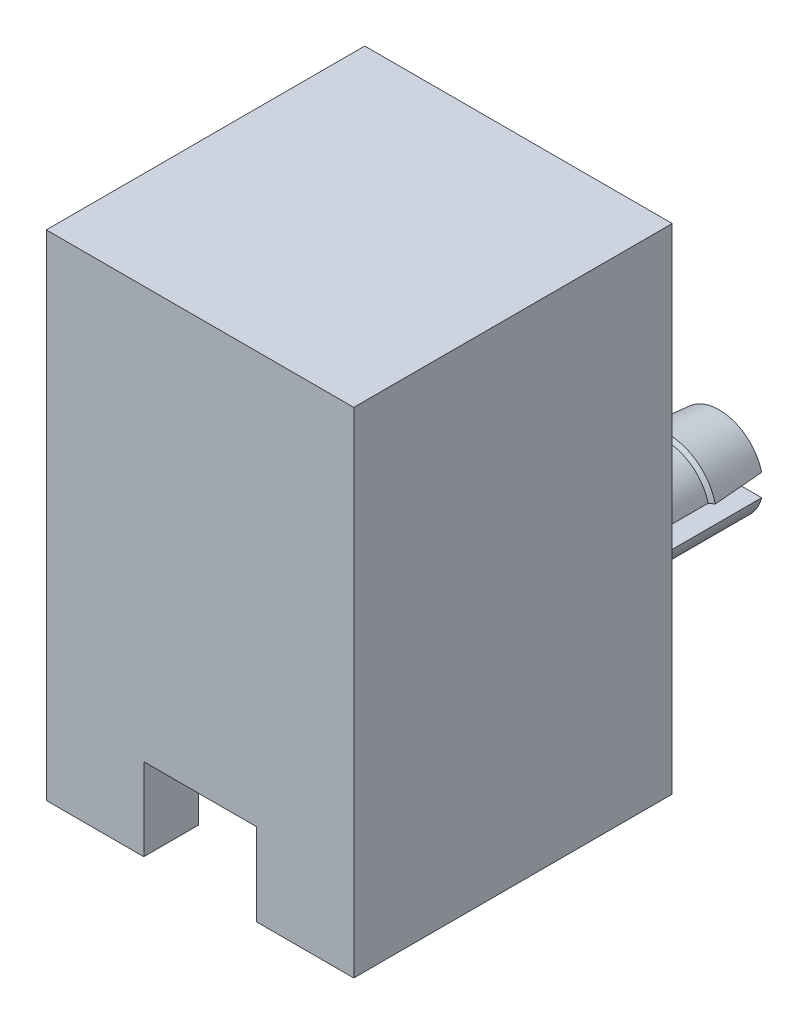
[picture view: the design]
ISO-10303-21;
HEADER;
FILE_DESCRIPTION(('STEP AP214'),'2;1');
FILE_NAME('part.step','',(''),(''),'','','');
FILE_SCHEMA(('AUTOMOTIVE_DESIGN { 1 0 10303 214 1 1 1 1 }'));
ENDSEC;
DATA;
#1=APPLICATION_CONTEXT('core data for automotive mechanical design processes');
#2=APPLICATION_PROTOCOL_DEFINITION('international standard','automotive_design',2000,#1);
#3=PRODUCT_CONTEXT('',#1,'mechanical');
#4=PRODUCT('Part','Part','',(#3));
#5=PRODUCT_RELATED_PRODUCT_CATEGORY('part','',(#4));
#6=PRODUCT_DEFINITION_FORMATION('','',#4);
#7=PRODUCT_DEFINITION_CONTEXT('part definition',#1,'design');
#8=PRODUCT_DEFINITION('design','',#6,#7);
#9=PRODUCT_DEFINITION_SHAPE('','',#8);
#10=(LENGTH_UNIT() NAMED_UNIT(*) SI_UNIT(.MILLI.,.METRE.));
#11=(NAMED_UNIT(*) PLANE_ANGLE_UNIT() SI_UNIT($,.RADIAN.));
#12=(NAMED_UNIT(*) SI_UNIT($,.STERADIAN.) SOLID_ANGLE_UNIT());
#13=UNCERTAINTY_MEASURE_WITH_UNIT(LENGTH_MEASURE(1.E-05),#10,'distance_accuracy_value','');
#14=(GEOMETRIC_REPRESENTATION_CONTEXT(3) GLOBAL_UNCERTAINTY_ASSIGNED_CONTEXT((#13)) GLOBAL_UNIT_ASSIGNED_CONTEXT((#10,
#11,#12)) REPRESENTATION_CONTEXT('',''));
#15=CARTESIAN_POINT('',(0.,0.,0.));
#16=DIRECTION('',(0.,0.,1.));
#17=DIRECTION('',(1.,0.,0.));
#18=AXIS2_PLACEMENT_3D('',#15,#16,#17);
#19=CARTESIAN_POINT('',(0.,0.,-9.3000000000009));
#20=DIRECTION('',(0.,0.,-1.));
#21=DIRECTION('',(-1.,0.,0.));
#22=AXIS2_PLACEMENT_3D('',#19,#20,#21);
#23=PLANE('',#22);
#24=DIRECTION('',(1.,0.,0.));
#25=VECTOR('',#24,1.);
#26=CARTESIAN_POINT('',(6.99772335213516,7.48000000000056,-9.3000000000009));
#27=LINE('',#26,#25);
#28=CARTESIAN_POINT('',(2.26080666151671,7.48000000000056,-9.3000000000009));
#29=VERTEX_POINT('',#28);
#30=CARTESIAN_POINT('',(5.35919333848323,7.48000000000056,-9.3000000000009));
#31=VERTEX_POINT('',#30);
#32=EDGE_CURVE('E484',#29,#31,#27,.T.);
#33=ORIENTED_EDGE('',*,*,#32,.T.);
#34=CARTESIAN_POINT('',(3.81,7.87999999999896,-9.3000000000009));
#35=DIRECTION('',(0.,0.,-1.));
#36=DIRECTION('',(-1.,0.,0.));
#37=AXIS2_PLACEMENT_3D('',#34,#35,#36);
#38=CIRCLE('',#37,1.59999999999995);
#39=EDGE_CURVE('E489',#29,#31,#38,.F.);
#40=ORIENTED_EDGE('',*,*,#39,.F.);
#41=EDGE_LOOP('',(#33,#40));
#42=FACE_BOUND('',#41,.T.);
#43=ADVANCED_FACE('F17',(#42),#23,.T.);
#44=CARTESIAN_POINT('',(0.,0.,-9.3000000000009));
#45=DIRECTION('',(0.,0.,-1.));
#46=DIRECTION('',(-1.,0.,0.));
#47=AXIS2_PLACEMENT_3D('',#44,#45,#46);
#48=PLANE('',#47);
#49=DIRECTION('',(1.,0.,0.));
#50=VECTOR('',#49,1.);
#51=CARTESIAN_POINT('',(6.99772335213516,7.48000000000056,-9.3000000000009));
#52=LINE('',#51,#50);
#53=CARTESIAN_POINT('',(-5.35919333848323,7.48000000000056,-9.3000000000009));
#54=VERTEX_POINT('',#53);
#55=CARTESIAN_POINT('',(-2.26080666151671,7.48000000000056,-9.3000000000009));
#56=VERTEX_POINT('',#55);
#57=EDGE_CURVE('E478',#54,#56,#52,.T.);
#58=ORIENTED_EDGE('',*,*,#57,.T.);
#59=CARTESIAN_POINT('',(-3.81,7.87999999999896,-9.3000000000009));
#60=DIRECTION('',(0.,0.,-1.));
#61=DIRECTION('',(-1.,0.,0.));
#62=AXIS2_PLACEMENT_3D('',#59,#60,#61);
#63=CIRCLE('',#62,1.59999999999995);
#64=EDGE_CURVE('E291',#54,#56,#63,.F.);
#65=ORIENTED_EDGE('',*,*,#64,.F.);
#66=EDGE_LOOP('',(#58,#65));
#67=FACE_BOUND('',#66,.T.);
#68=ADVANCED_FACE('F309',(#67),#48,.T.);
#69=CARTESIAN_POINT('',(-3.81,7.87999999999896,-7.45365044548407));
#70=DIRECTION('',(0.,0.,-1.));
#71=DIRECTION('',(-1.,0.,0.));
#72=AXIS2_PLACEMENT_3D('',#69,#70,#71);
#73=CONICAL_SURFACE('',#72,1.74999999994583,0.966134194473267);
#74=CARTESIAN_POINT('',(-5.51367250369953,8.2799999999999,-7.45365044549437));
#75=CARTESIAN_POINT('',(-5.48794766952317,8.2799999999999,-7.43634304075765));
#76=CARTESIAN_POINT('',(-5.46221198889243,8.2799999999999,-7.41905180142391));
#77=CARTESIAN_POINT('',(-5.4107189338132,8.2799999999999,-7.3845016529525));
#78=CARTESIAN_POINT('',(-5.38496155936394,8.2799999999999,-7.36724274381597));
#79=CARTESIAN_POINT('',(-5.35919333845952,8.2799999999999,-7.35000000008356));
#80=B_SPLINE_CURVE_WITH_KNOTS('',3,(#74,#75,#76,#77,#78,#79),.UNSPECIFIED.,.F.,.F.,(4,2,4),(0.,
0.0930151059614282,0.186030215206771),.UNSPECIFIED.);
#81=CARTESIAN_POINT('',(-5.5136725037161,8.2799999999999,-7.45365044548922));
#82=VERTEX_POINT('',#81);
#83=CARTESIAN_POINT('',(-5.35919333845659,8.2799999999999,-7.35000000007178));
#84=VERTEX_POINT('',#83);
#85=EDGE_CURVE('E263',#82,#84,#80,.T.);
#86=ORIENTED_EDGE('',*,*,#85,.T.);
#87=CARTESIAN_POINT('',(-3.81,7.87999999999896,-7.35000000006));
#88=DIRECTION('',(0.,0.,-1.));
#89=DIRECTION('',(-1.,0.,0.));
#90=AXIS2_PLACEMENT_3D('',#87,#88,#89);
#91=CIRCLE('',#90,1.59999999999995);
#92=CARTESIAN_POINT('',(-2.26080666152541,8.2799999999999,-7.35000000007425));
#93=VERTEX_POINT('',#92);
#94=EDGE_CURVE('E261',#93,#84,#91,.F.);
#95=ORIENTED_EDGE('',*,*,#94,.F.);
#96=CARTESIAN_POINT('',(-2.26080666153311,8.2799999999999,-7.3500000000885));
#97=CARTESIAN_POINT('',(-2.23503844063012,8.2799999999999,-7.36724274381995));
#98=CARTESIAN_POINT('',(-2.20928106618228,8.2799999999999,-7.38450165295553));
#99=CARTESIAN_POINT('',(-2.1577880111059,8.2799999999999,-7.41905180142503));
#100=CARTESIAN_POINT('',(-2.13205233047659,8.2799999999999,-7.43634304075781));
#101=CARTESIAN_POINT('',(-2.10632749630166,8.2799999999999,-7.45365044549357));
#102=B_SPLINE_CURVE_WITH_KNOTS('',3,(#96,#97,#98,#99,#100,#101),.UNSPECIFIED.,.F.,.F.,(4,2,4),
(0.,0.0930151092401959,0.186030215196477),.UNSPECIFIED.);
#103=CARTESIAN_POINT('',(-2.10632749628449,8.2799999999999,-7.45365044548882));
#104=VERTEX_POINT('',#103);
#105=EDGE_CURVE('E20',#93,#104,#102,.T.);
#106=ORIENTED_EDGE('',*,*,#105,.T.);
#107=CARTESIAN_POINT('',(-3.81,7.87999999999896,-7.45365044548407));
#108=DIRECTION('',(0.,0.,1.));
#109=DIRECTION('',(0.,-1.,0.));
#110=AXIS2_PLACEMENT_3D('',#107,#108,#109);
#111=CIRCLE('',#110,1.749999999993);
#112=EDGE_CURVE('E258',#82,#104,#111,.F.);
#113=ORIENTED_EDGE('',*,*,#112,.F.);
#114=EDGE_LOOP('',(#86,#95,#106,#113));
#115=FACE_BOUND('',#114,.T.);
#116=ADVANCED_FACE('F257',(#115),#73,.T.);
#117=CARTESIAN_POINT('',(0.,0.,-9.3000000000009));
#118=DIRECTION('',(0.,0.,-1.));
#119=DIRECTION('',(-1.,0.,0.));
#120=AXIS2_PLACEMENT_3D('',#117,#118,#119);
#121=PLANE('',#120);
#122=DIRECTION('',(1.,0.,0.));
#123=VECTOR('',#122,1.);
#124=CARTESIAN_POINT('',(-6.92386875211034,8.2799999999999,-9.29999999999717));
#125=LINE('',#124,#123);
#126=CARTESIAN_POINT('',(-2.26080666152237,8.2799999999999,-9.29999999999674));
#127=VERTEX_POINT('',#126);
#128=CARTESIAN_POINT('',(-5.35919333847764,8.2799999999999,-9.29999999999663));
#129=VERTEX_POINT('',#128);
#130=EDGE_CURVE('E276',#127,#129,#125,.F.);
#131=ORIENTED_EDGE('',*,*,#130,.T.);
#132=CARTESIAN_POINT('',(-3.81,7.87999999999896,-9.29999999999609));
#133=DIRECTION('',(0.,0.,1.));
#134=DIRECTION('',(0.,-1.,0.));
#135=AXIS2_PLACEMENT_3D('',#132,#133,#134);
#136=CIRCLE('',#135,1.59999999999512);
#137=EDGE_CURVE('E273',#127,#129,#136,.T.);
#138=ORIENTED_EDGE('',*,*,#137,.F.);
#139=EDGE_LOOP('',(#131,#138));
#140=FACE_BOUND('',#139,.T.);
#141=ADVANCED_FACE('F301',(#140),#121,.T.);
#142=CARTESIAN_POINT('',(-3.81,7.87999999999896,-7.45365044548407));
#143=DIRECTION('',(0.,0.,1.));
#144=DIRECTION('',(0.,-1.,0.));
#145=AXIS2_PLACEMENT_3D('',#142,#143,#144);
#146=CONICAL_SURFACE('',#145,1.749999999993,0.081063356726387);
#147=CARTESIAN_POINT('',(-5.35919333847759,8.2799999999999,-9.29999999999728));
#148=CARTESIAN_POINT('',(-5.38500925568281,8.2799999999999,-8.99228087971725));
#149=CARTESIAN_POINT('',(-5.410790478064,8.2799999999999,-8.68455885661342));
#150=CARTESIAN_POINT('',(-5.46228353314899,8.2799999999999,-8.06910900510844));
#151=CARTESIAN_POINT('',(-5.48799536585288,8.2799999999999,-7.7613811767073));
#152=CARTESIAN_POINT('',(-5.51367250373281,8.2799999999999,-7.45365044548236));
#153=B_SPLINE_CURVE_WITH_KNOTS('',3,(#147,#148,#149,#150,#151,#152),.UNSPECIFIED.,.F.,.F.,(4,2,
4),(0.,0.926400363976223,1.8528007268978),.UNSPECIFIED.);
#154=EDGE_CURVE('E271',#129,#82,#153,.T.);
#155=ORIENTED_EDGE('',*,*,#154,.T.);
#156=ORIENTED_EDGE('',*,*,#112,.T.);
#157=CARTESIAN_POINT('',(-2.10632749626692,8.2799999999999,-7.45365044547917));
#158=CARTESIAN_POINT('',(-2.1320046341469,8.2799999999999,-7.76138117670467));
#159=CARTESIAN_POINT('',(-2.15771646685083,8.2799999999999,-8.06910900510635));
#160=CARTESIAN_POINT('',(-2.20920952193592,8.2799999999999,-8.68455885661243));
#161=CARTESIAN_POINT('',(-2.23499074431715,8.2799999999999,-8.99228087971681));
#162=CARTESIAN_POINT('',(-2.26080666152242,8.2799999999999,-9.29999999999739));
#163=B_SPLINE_CURVE_WITH_KNOTS('',3,(#157,#158,#159,#160,#161,#162),.UNSPECIFIED.,.F.,.F.,(4,2,
4),(0.,0.926400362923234,1.85280072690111),.UNSPECIFIED.);
#164=EDGE_CURVE('E268',#104,#127,#163,.T.);
#165=ORIENTED_EDGE('',*,*,#164,.T.);
#166=ORIENTED_EDGE('',*,*,#137,.T.);
#167=EDGE_LOOP('',(#155,#156,#165,#166));
#168=FACE_BOUND('',#167,.T.);
#169=ADVANCED_FACE('F266',(#168),#146,.T.);
#170=CARTESIAN_POINT('',(3.81,7.87999999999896,-7.45365044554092));
#171=DIRECTION('',(0.,0.,-1.));
#172=DIRECTION('',(0.,1.,0.));
#173=AXIS2_PLACEMENT_3D('',#170,#171,#172);
#174=CONICAL_SURFACE('',#173,1.75000000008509,0.966134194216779);
#175=CARTESIAN_POINT('',(5.35919333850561,8.2799999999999,-7.35000000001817));
#176=CARTESIAN_POINT('',(5.38496155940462,8.2799999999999,-7.36724274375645));
#177=CARTESIAN_POINT('',(5.41071893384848,8.2799999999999,-7.38450165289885));
#178=CARTESIAN_POINT('',(5.46221198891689,8.2799999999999,-7.41905180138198));
#179=CARTESIAN_POINT('',(5.48794766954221,8.2799999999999,-7.43634304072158));
#180=CARTESIAN_POINT('',(5.51367250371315,8.2799999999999,-7.45365044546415));
#181=B_SPLINE_CURVE_WITH_KNOTS('',3,(#175,#176,#177,#178,#179,#180),.UNSPECIFIED.,.F.,.F.,(4,2,
4),(0.,0.0930151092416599,0.186030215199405),.UNSPECIFIED.);
#182=CARTESIAN_POINT('',(5.3591933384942,8.2799999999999,-7.34999999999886));
#183=VERTEX_POINT('',#182);
#184=CARTESIAN_POINT('',(5.51367250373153,8.2799999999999,-7.45365044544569));
#185=VERTEX_POINT('',#184);
#186=EDGE_CURVE('E321',#183,#185,#181,.T.);
#187=ORIENTED_EDGE('',*,*,#186,.T.);
#188=CARTESIAN_POINT('',(3.81,7.87999999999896,-7.45365044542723));
#189=DIRECTION('',(0.,0.,1.));
#190=DIRECTION('',(1.,0.,0.));
#191=AXIS2_PLACEMENT_3D('',#188,#189,#190);
#192=CIRCLE('',#191,1.75000000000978);
#193=CARTESIAN_POINT('',(2.1063274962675,8.2799999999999,-7.45365044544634));
#194=VERTEX_POINT('',#193);
#195=EDGE_CURVE('E538',#194,#185,#192,.F.);
#196=ORIENTED_EDGE('',*,*,#195,.F.);
#197=CARTESIAN_POINT('',(2.10632749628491,8.2799999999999,-7.45365044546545));
#198=CARTESIAN_POINT('',(2.1320523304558,8.2799999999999,-7.43634304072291));
#199=CARTESIAN_POINT('',(2.15778801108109,8.2799999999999,-7.41905180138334));
#200=CARTESIAN_POINT('',(2.20928106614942,8.2799999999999,-7.38450165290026));
#201=CARTESIAN_POINT('',(2.23503844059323,8.2799999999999,-7.36724274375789));
#202=CARTESIAN_POINT('',(2.2608066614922,8.2799999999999,-7.35000000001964));
#203=B_SPLINE_CURVE_WITH_KNOTS('',3,(#197,#198,#199,#200,#201,#202),.UNSPECIFIED.,.F.,.F.,(4,2,
4),(0.,0.0930151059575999,0.186030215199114),.UNSPECIFIED.);
#204=CARTESIAN_POINT('',(2.26080666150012,8.2799999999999,-7.34999999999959));
#205=VERTEX_POINT('',#204);
#206=EDGE_CURVE('E272',#194,#205,#203,.T.);
#207=ORIENTED_EDGE('',*,*,#206,.T.);
#208=CARTESIAN_POINT('',(3.81,7.87999999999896,-7.34999999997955));
#209=DIRECTION('',(0.,0.,-1.));
#210=DIRECTION('',(-1.,0.,0.));
#211=AXIS2_PLACEMENT_3D('',#208,#209,#210);
#212=CIRCLE('',#211,1.59999999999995);
#213=EDGE_CURVE('E472',#183,#205,#212,.F.);
#214=ORIENTED_EDGE('',*,*,#213,.F.);
#215=EDGE_LOOP('',(#187,#196,#207,#214));
#216=FACE_BOUND('',#215,.T.);
#217=ADVANCED_FACE('F300',(#216),#174,.T.);
#218=CARTESIAN_POINT('',(0.,0.,-9.3000000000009));
#219=DIRECTION('',(0.,0.,-1.));
#220=DIRECTION('',(-1.,0.,0.));
#221=AXIS2_PLACEMENT_3D('',#218,#219,#220);
#222=PLANE('',#221);
#223=DIRECTION('',(1.,0.,0.));
#224=VECTOR('',#223,1.);
#225=CARTESIAN_POINT('',(-6.92386875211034,8.2799999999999,-9.29999999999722));
#226=LINE('',#225,#224);
#227=CARTESIAN_POINT('',(5.35919333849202,8.2799999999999,-9.29999999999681));
#228=VERTEX_POINT('',#227);
#229=CARTESIAN_POINT('',(2.26080666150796,8.2799999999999,-9.29999999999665));
#230=VERTEX_POINT('',#229);
#231=EDGE_CURVE('E349',#228,#230,#226,.F.);
#232=ORIENTED_EDGE('',*,*,#231,.T.);
#233=CARTESIAN_POINT('',(3.81,7.87999999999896,-9.29999999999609));
#234=DIRECTION('',(0.,0.,1.));
#235=DIRECTION('',(1.,0.,0.));
#236=AXIS2_PLACEMENT_3D('',#233,#234,#235);
#237=CIRCLE('',#236,1.60000000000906);
#238=EDGE_CURVE('E534',#228,#230,#237,.T.);
#239=ORIENTED_EDGE('',*,*,#238,.F.);
#240=EDGE_LOOP('',(#232,#239));
#241=FACE_BOUND('',#240,.T.);
#242=ADVANCED_FACE('F356',(#241),#222,.T.);
#243=CARTESIAN_POINT('',(3.81,7.87999999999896,-7.45365044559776));
#244=DIRECTION('',(0.,0.,1.));
#245=DIRECTION('',(1.,0.,0.));
#246=AXIS2_PLACEMENT_3D('',#243,#244,#245);
#247=CONICAL_SURFACE('',#246,1.74999999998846,0.0810633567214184);
#248=CARTESIAN_POINT('',(5.51367250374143,8.2799999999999,-7.45365044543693));
#249=CARTESIAN_POINT('',(5.48799536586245,8.2799999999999,-7.76138117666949));
#250=CARTESIAN_POINT('',(5.46228353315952,8.2799999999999,-8.06910900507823));
#251=CARTESIAN_POINT('',(5.41079047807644,8.2799999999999,-8.68455885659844));
#252=CARTESIAN_POINT('',(5.38500925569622,8.2799999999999,-8.99228087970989));
#253=CARTESIAN_POINT('',(5.35919333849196,8.2799999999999,-9.29999999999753));
#254=B_SPLINE_CURVE_WITH_KNOTS('',3,(#248,#249,#250,#251,#252,#253),.UNSPECIFIED.,.F.,.F.,(4,2,
4),(0.,0.926400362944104,1.85280072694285),.UNSPECIFIED.);
#255=EDGE_CURVE('E344',#185,#228,#254,.T.);
#256=ORIENTED_EDGE('',*,*,#255,.T.);
#257=ORIENTED_EDGE('',*,*,#238,.T.);
#258=CARTESIAN_POINT('',(2.26080666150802,8.2799999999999,-9.2999999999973));
#259=CARTESIAN_POINT('',(2.23499074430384,8.2799999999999,-8.99228087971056));
#260=CARTESIAN_POINT('',(2.20920952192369,8.2799999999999,-8.6845588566));
#261=CARTESIAN_POINT('',(2.15771646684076,8.2799999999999,-8.06910900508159));
#262=CARTESIAN_POINT('',(2.1320046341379,8.2799999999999,-7.76138117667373));
#263=CARTESIAN_POINT('',(2.106327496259,8.2799999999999,-7.45365044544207));
#264=B_SPLINE_CURVE_WITH_KNOTS('',3,(#258,#259,#260,#261,#262,#263),.UNSPECIFIED.,.F.,.F.,(4,2,
4),(0.,0.926400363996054,1.85280072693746),.UNSPECIFIED.);
#265=EDGE_CURVE('E338',#230,#194,#264,.T.);
#266=ORIENTED_EDGE('',*,*,#265,.T.);
#267=ORIENTED_EDGE('',*,*,#195,.T.);
#268=EDGE_LOOP('',(#256,#257,#266,#267));
#269=FACE_BOUND('',#268,.T.);
#270=ADVANCED_FACE('F351',(#269),#247,.T.);
#271=CARTESIAN_POINT('',(2.9000000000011,0.,-3.0000000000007));
#272=DIRECTION('',(0.,0.,-1.));
#273=DIRECTION('',(-1.,0.,0.));
#274=AXIS2_PLACEMENT_3D('',#271,#272,#273);
#275=PLANE('',#274);
#276=DIRECTION('',(1.,0.,0.));
#277=VECTOR('',#276,1.);
#278=CARTESIAN_POINT('',(0.,10.0000000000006,-3.0000000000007));
#279=LINE('',#278,#277);
#280=CARTESIAN_POINT('',(2.9000000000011,10.0000000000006,-3.0000000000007));
#281=VERTEX_POINT('',#280);
#282=CARTESIAN_POINT('',(3.99999999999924,10.0000000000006,-3.0000000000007));
#283=VERTEX_POINT('',#282);
#284=EDGE_CURVE('E527',#281,#283,#279,.T.);
#285=ORIENTED_EDGE('',*,*,#284,.F.);
#286=DIRECTION('',(0.,1.,0.));
#287=VECTOR('',#286,1.);
#288=CARTESIAN_POINT('',(2.9000000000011,0.,-3.0000000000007));
#289=LINE('',#288,#287);
#290=CARTESIAN_POINT('',(2.9000000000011,0.,-3.0000000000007));
#291=VERTEX_POINT('',#290);
#292=EDGE_CURVE('E460',#281,#291,#289,.F.);
#293=ORIENTED_EDGE('',*,*,#292,.T.);
#294=DIRECTION('',(-1.,0.,0.));
#295=VECTOR('',#294,1.);
#296=CARTESIAN_POINT('',(2.9000000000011,0.,-3.0000000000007));
#297=LINE('',#296,#295);
#298=CARTESIAN_POINT('',(3.99999999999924,0.,-3.0000000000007));
#299=VERTEX_POINT('',#298);
#300=EDGE_CURVE('E532',#299,#291,#297,.T.);
#301=ORIENTED_EDGE('',*,*,#300,.F.);
#302=DIRECTION('',(0.,1.,0.));
#303=VECTOR('',#302,1.);
#304=CARTESIAN_POINT('',(3.99999999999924,0.,-3.0000000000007));
#305=LINE('',#304,#303);
#306=EDGE_CURVE('E518',#299,#283,#305,.T.);
#307=ORIENTED_EDGE('',*,*,#306,.T.);
#308=EDGE_LOOP('',(#285,#293,#301,#307));
#309=FACE_BOUND('',#308,.T.);
#310=ADVANCED_FACE('F355',(#309),#275,.F.);
#311=CARTESIAN_POINT('',(-3.99999999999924,0.,-3.0000000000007));
#312=DIRECTION('',(0.,0.,-1.));
#313=DIRECTION('',(-1.,0.,0.));
#314=AXIS2_PLACEMENT_3D('',#311,#312,#313);
#315=PLANE('',#314);
#316=DIRECTION('',(1.,0.,0.));
#317=VECTOR('',#316,1.);
#318=CARTESIAN_POINT('',(0.,10.0000000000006,-3.0000000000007));
#319=LINE('',#318,#317);
#320=CARTESIAN_POINT('',(-3.99999999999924,10.0000000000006,-3.0000000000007));
#321=VERTEX_POINT('',#320);
#322=CARTESIAN_POINT('',(-2.9000000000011,10.0000000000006,-3.0000000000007));
#323=VERTEX_POINT('',#322);
#324=EDGE_CURVE('E524',#321,#323,#319,.T.);
#325=ORIENTED_EDGE('',*,*,#324,.F.);
#326=DIRECTION('',(0.,1.,0.));
#327=VECTOR('',#326,1.);
#328=CARTESIAN_POINT('',(-3.99999999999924,0.,-3.0000000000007));
#329=LINE('',#328,#327);
#330=CARTESIAN_POINT('',(-3.99999999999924,0.,-3.0000000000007));
#331=VERTEX_POINT('',#330);
#332=EDGE_CURVE('E500',#321,#331,#329,.F.);
#333=ORIENTED_EDGE('',*,*,#332,.T.);
#334=DIRECTION('',(-1.,0.,0.));
#335=VECTOR('',#334,1.);
#336=CARTESIAN_POINT('',(-3.99999999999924,0.,-3.0000000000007));
#337=LINE('',#336,#335);
#338=CARTESIAN_POINT('',(-2.9000000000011,0.,-3.0000000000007));
#339=VERTEX_POINT('',#338);
#340=EDGE_CURVE('E530',#339,#331,#337,.T.);
#341=ORIENTED_EDGE('',*,*,#340,.F.);
#342=DIRECTION('',(0.,1.,0.));
#343=VECTOR('',#342,1.);
#344=CARTESIAN_POINT('',(-2.9000000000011,0.,-3.0000000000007));
#345=LINE('',#344,#343);
#346=EDGE_CURVE('E452',#339,#323,#345,.T.);
#347=ORIENTED_EDGE('',*,*,#346,.T.);
#348=EDGE_LOOP('',(#325,#333,#341,#347));
#349=FACE_BOUND('',#348,.T.);
#350=ADVANCED_FACE('F726',(#349),#315,.F.);
#351=CARTESIAN_POINT('',(0.,10.0000000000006,0.));
#352=DIRECTION('',(0.,-1.,0.));
#353=DIRECTION('',(0.,0.,-1.));
#354=AXIS2_PLACEMENT_3D('',#351,#352,#353);
#355=PLANE('',#354);
#356=DIRECTION('',(0.,0.,1.));
#357=VECTOR('',#356,1.);
#358=CARTESIAN_POINT('',(-2.9000000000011,10.0000000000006,-3.0000000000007));
#359=LINE('',#358,#357);
#360=CARTESIAN_POINT('',(-2.9000000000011,10.0000000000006,-4.80000000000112));
#361=VERTEX_POINT('',#360);
#362=EDGE_CURVE('E447',#323,#361,#359,.F.);
#363=ORIENTED_EDGE('',*,*,#362,.T.);
#364=DIRECTION('',(-1.,0.,0.));
#365=VECTOR('',#364,1.);
#366=CARTESIAN_POINT('',(-2.9000000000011,10.0000000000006,-4.80000000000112));
#367=LINE('',#366,#365);
#368=CARTESIAN_POINT('',(2.9000000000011,10.0000000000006,-4.80000000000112));
#369=VERTEX_POINT('',#368);
#370=EDGE_CURVE('E522',#361,#369,#367,.F.);
#371=ORIENTED_EDGE('',*,*,#370,.T.);
#372=DIRECTION('',(0.,0.,-1.));
#373=VECTOR('',#372,1.);
#374=CARTESIAN_POINT('',(2.9000000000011,10.0000000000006,-4.80000000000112));
#375=LINE('',#374,#373);
#376=EDGE_CURVE('E463',#369,#281,#375,.F.);
#377=ORIENTED_EDGE('',*,*,#376,.T.);
#378=ORIENTED_EDGE('',*,*,#284,.T.);
#379=DIRECTION('',(0.,0.,-1.));
#380=VECTOR('',#379,1.);
#381=CARTESIAN_POINT('',(3.99999999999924,10.0000000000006,-3.0000000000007));
#382=LINE('',#381,#380);
#383=CARTESIAN_POINT('',(3.99999999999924,10.0000000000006,3.80000000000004));
#384=VERTEX_POINT('',#383);
#385=EDGE_CURVE('E516',#283,#384,#382,.F.);
#386=ORIENTED_EDGE('',*,*,#385,.T.);
#387=DIRECTION('',(1.,0.,0.));
#388=VECTOR('',#387,1.);
#389=CARTESIAN_POINT('',(3.99999999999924,10.0000000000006,3.80000000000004));
#390=LINE('',#389,#388);
#391=CARTESIAN_POINT('',(-3.99999999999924,10.0000000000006,3.80000000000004));
#392=VERTEX_POINT('',#391);
#393=EDGE_CURVE('E512',#384,#392,#390,.F.);
#394=ORIENTED_EDGE('',*,*,#393,.T.);
#395=DIRECTION('',(0.,0.,1.));
#396=VECTOR('',#395,1.);
#397=CARTESIAN_POINT('',(-3.99999999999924,10.0000000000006,3.80000000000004));
#398=LINE('',#397,#396);
#399=EDGE_CURVE('E503',#392,#321,#398,.F.);
#400=ORIENTED_EDGE('',*,*,#399,.T.);
#401=ORIENTED_EDGE('',*,*,#324,.T.);
#402=EDGE_LOOP('',(#363,#371,#377,#378,#386,#394,#400,#401));
#403=FACE_BOUND('',#402,.T.);
#404=ADVANCED_FACE('F724',(#403),#355,.T.);
#405=CARTESIAN_POINT('',(-2.9000000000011,0.,-4.80000000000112));
#406=DIRECTION('',(0.,0.,-1.));
#407=DIRECTION('',(-1.,0.,0.));
#408=AXIS2_PLACEMENT_3D('',#405,#406,#407);
#409=PLANE('',#408);
#410=ORIENTED_EDGE('',*,*,#370,.F.);
#411=DIRECTION('',(0.,1.,0.));
#412=VECTOR('',#411,1.);
#413=CARTESIAN_POINT('',(-2.9000000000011,0.,-4.80000000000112));
#414=LINE('',#413,#412);
#415=CARTESIAN_POINT('',(-2.9000000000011,4.80000000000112,-4.80000000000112));
#416=VERTEX_POINT('',#415);
#417=EDGE_CURVE('E439',#361,#416,#414,.F.);
#418=ORIENTED_EDGE('',*,*,#417,.T.);
#419=DIRECTION('',(1.,0.,0.));
#420=VECTOR('',#419,1.);
#421=CARTESIAN_POINT('',(-2.9000000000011,4.80000000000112,-4.80000000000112));
#422=LINE('',#421,#420);
#423=CARTESIAN_POINT('',(2.9000000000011,4.80000000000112,-4.80000000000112));
#424=VERTEX_POINT('',#423);
#425=EDGE_CURVE('E426',#416,#424,#422,.T.);
#426=ORIENTED_EDGE('',*,*,#425,.T.);
#427=DIRECTION('',(0.,1.,0.));
#428=VECTOR('',#427,1.);
#429=CARTESIAN_POINT('',(2.9000000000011,0.,-4.80000000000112));
#430=LINE('',#429,#428);
#431=EDGE_CURVE('E466',#424,#369,#430,.T.);
#432=ORIENTED_EDGE('',*,*,#431,.T.);
#433=EDGE_LOOP('',(#410,#418,#426,#432));
#434=FACE_BOUND('',#433,.T.);
#435=ADVANCED_FACE('F720',(#434),#409,.F.);
#436=CARTESIAN_POINT('',(-2.9000000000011,0.,-4.80000000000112));
#437=DIRECTION('',(0.,0.,-1.));
#438=DIRECTION('',(-1.,0.,0.));
#439=AXIS2_PLACEMENT_3D('',#436,#437,#438);
#440=PLANE('',#439);
#441=DIRECTION('',(0.,1.,0.));
#442=VECTOR('',#441,1.);
#443=CARTESIAN_POINT('',(-2.9000000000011,0.,-4.80000000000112));
#444=LINE('',#443,#442);
#445=CARTESIAN_POINT('',(-2.9000000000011,1.79999999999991,-4.80000000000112));
#446=VERTEX_POINT('',#445);
#447=CARTESIAN_POINT('',(-2.9000000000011,0.,-4.80000000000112));
#448=VERTEX_POINT('',#447);
#449=EDGE_CURVE('E454',#446,#448,#444,.F.);
#450=ORIENTED_EDGE('',*,*,#449,.T.);
#451=DIRECTION('',(-1.,0.,0.));
#452=VECTOR('',#451,1.);
#453=CARTESIAN_POINT('',(-2.9000000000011,0.,-4.80000000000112));
#454=LINE('',#453,#452);
#455=CARTESIAN_POINT('',(-1.5000000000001,0.,-4.80000000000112));
#456=VERTEX_POINT('',#455);
#457=EDGE_CURVE('E520',#456,#448,#454,.T.);
#458=ORIENTED_EDGE('',*,*,#457,.F.);
#459=DIRECTION('',(0.,1.,0.));
#460=VECTOR('',#459,1.);
#461=CARTESIAN_POINT('',(-1.5000000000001,-1.18255143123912,-4.80000000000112));
#462=LINE('',#461,#460);
#463=CARTESIAN_POINT('',(-1.5000000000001,1.79999999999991,-4.80000000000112));
#464=VERTEX_POINT('',#463);
#465=EDGE_CURVE('E626',#456,#464,#462,.T.);
#466=ORIENTED_EDGE('',*,*,#465,.T.);
#467=DIRECTION('',(1.,0.,0.));
#468=VECTOR('',#467,1.);
#469=CARTESIAN_POINT('',(-1.5000000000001,1.79999999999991,-4.80000000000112));
#470=LINE('',#469,#468);
#471=EDGE_CURVE('E443',#464,#446,#470,.F.);
#472=ORIENTED_EDGE('',*,*,#471,.T.);
#473=EDGE_LOOP('',(#450,#458,#466,#472));
#474=FACE_BOUND('',#473,.T.);
#475=ADVANCED_FACE('F716',(#474),#440,.F.);
#476=CARTESIAN_POINT('',(3.99999999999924,0.,-3.0000000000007));
#477=DIRECTION('',(1.,0.,0.));
#478=DIRECTION('',(0.,0.,-1.));
#479=AXIS2_PLACEMENT_3D('',#476,#477,#478);
#480=PLANE('',#479);
#481=ORIENTED_EDGE('',*,*,#385,.F.);
#482=ORIENTED_EDGE('',*,*,#306,.F.);
#483=DIRECTION('',(0.,0.,1.));
#484=VECTOR('',#483,1.);
#485=CARTESIAN_POINT('',(3.99999999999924,0.,0.));
#486=LINE('',#485,#484);
#487=CARTESIAN_POINT('',(3.99999999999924,0.,3.80000000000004));
#488=VERTEX_POINT('',#487);
#489=EDGE_CURVE('E619',#299,#488,#486,.T.);
#490=ORIENTED_EDGE('',*,*,#489,.T.);
#491=DIRECTION('',(0.,1.,0.));
#492=VECTOR('',#491,1.);
#493=CARTESIAN_POINT('',(3.99999999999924,0.,3.80000000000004));
#494=LINE('',#493,#492);
#495=EDGE_CURVE('E509',#488,#384,#494,.T.);
#496=ORIENTED_EDGE('',*,*,#495,.T.);
#497=EDGE_LOOP('',(#481,#482,#490,#496));
#498=FACE_BOUND('',#497,.T.);
#499=ADVANCED_FACE('F712',(#498),#480,.F.);
#500=CARTESIAN_POINT('',(-2.9000000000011,0.,-4.80000000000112));
#501=DIRECTION('',(0.,0.,-1.));
#502=DIRECTION('',(-1.,0.,0.));
#503=AXIS2_PLACEMENT_3D('',#500,#501,#502);
#504=PLANE('',#503);
#505=DIRECTION('',(1.,0.,0.));
#506=VECTOR('',#505,1.);
#507=CARTESIAN_POINT('',(0.,0.,-4.80000000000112));
#508=LINE('',#507,#506);
#509=CARTESIAN_POINT('',(1.5000000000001,0.,-4.80000000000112));
#510=VERTEX_POINT('',#509);
#511=CARTESIAN_POINT('',(2.9000000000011,0.,-4.80000000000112));
#512=VERTEX_POINT('',#511);
#513=EDGE_CURVE('E610',#510,#512,#508,.T.);
#514=ORIENTED_EDGE('',*,*,#513,.T.);
#515=DIRECTION('',(0.,1.,0.));
#516=VECTOR('',#515,1.);
#517=CARTESIAN_POINT('',(2.9000000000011,0.,-4.80000000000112));
#518=LINE('',#517,#516);
#519=CARTESIAN_POINT('',(2.9000000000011,1.79999999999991,-4.80000000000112));
#520=VERTEX_POINT('',#519);
#521=EDGE_CURVE('E435',#512,#520,#518,.T.);
#522=ORIENTED_EDGE('',*,*,#521,.T.);
#523=DIRECTION('',(-1.,0.,0.));
#524=VECTOR('',#523,1.);
#525=CARTESIAN_POINT('',(-2.9000000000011,1.79999999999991,-4.80000000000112));
#526=LINE('',#525,#524);
#527=CARTESIAN_POINT('',(1.5000000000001,1.79999999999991,-4.80000000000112));
#528=VERTEX_POINT('',#527);
#529=EDGE_CURVE('E514',#528,#520,#526,.F.);
#530=ORIENTED_EDGE('',*,*,#529,.F.);
#531=DIRECTION('',(0.,1.,0.));
#532=VECTOR('',#531,1.);
#533=CARTESIAN_POINT('',(1.5000000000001,1.79999999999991,-4.80000000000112));
#534=LINE('',#533,#532);
#535=EDGE_CURVE('E605',#528,#510,#534,.F.);
#536=ORIENTED_EDGE('',*,*,#535,.T.);
#537=EDGE_LOOP('',(#514,#522,#530,#536));
#538=FACE_BOUND('',#537,.T.);
#539=ADVANCED_FACE('F708',(#538),#504,.F.);
#540=CARTESIAN_POINT('',(3.99999999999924,0.,3.80000000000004));
#541=DIRECTION('',(0.,0.,1.));
#542=DIRECTION('',(1.,0.,0.));
#543=AXIS2_PLACEMENT_3D('',#540,#541,#542);
#544=PLANE('',#543);
#545=DIRECTION('',(1.,0.,0.));
#546=VECTOR('',#545,1.);
#547=CARTESIAN_POINT('',(0.,0.,3.80000000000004));
#548=LINE('',#547,#546);
#549=CARTESIAN_POINT('',(2.04999999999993,0.,3.80000000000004));
#550=VERTEX_POINT('',#549);
#551=EDGE_CURVE('E617',#488,#550,#548,.F.);
#552=ORIENTED_EDGE('',*,*,#551,.T.);
#553=DIRECTION('',(0.,1.,0.));
#554=VECTOR('',#553,1.);
#555=CARTESIAN_POINT('',(2.04999999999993,0.,3.80000000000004));
#556=LINE('',#555,#554);
#557=CARTESIAN_POINT('',(2.04999999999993,3.0000000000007,3.80000000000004));
#558=VERTEX_POINT('',#557);
#559=EDGE_CURVE('E490',#550,#558,#556,.T.);
#560=ORIENTED_EDGE('',*,*,#559,.T.);
#561=DIRECTION('',(1.,0.,0.));
#562=VECTOR('',#561,1.);
#563=CARTESIAN_POINT('',(0.,3.0000000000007,3.80000000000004));
#564=LINE('',#563,#562);
#565=CARTESIAN_POINT('',(-2.04999999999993,3.0000000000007,3.80000000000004));
#566=VERTEX_POINT('',#565);
#567=EDGE_CURVE('E492',#566,#558,#564,.T.);
#568=ORIENTED_EDGE('',*,*,#567,.F.);
#569=DIRECTION('',(0.,1.,0.));
#570=VECTOR('',#569,1.);
#571=CARTESIAN_POINT('',(-2.04999999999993,0.,3.80000000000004));
#572=LINE('',#571,#570);
#573=CARTESIAN_POINT('',(-2.04999999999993,0.,3.80000000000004));
#574=VERTEX_POINT('',#573);
#575=EDGE_CURVE('E498',#566,#574,#572,.F.);
#576=ORIENTED_EDGE('',*,*,#575,.T.);
#577=DIRECTION('',(1.,0.,0.));
#578=VECTOR('',#577,1.);
#579=CARTESIAN_POINT('',(0.,0.,3.80000000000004));
#580=LINE('',#579,#578);
#581=CARTESIAN_POINT('',(-3.99999999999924,0.,3.80000000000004));
#582=VERTEX_POINT('',#581);
#583=EDGE_CURVE('E593',#574,#582,#580,.F.);
#584=ORIENTED_EDGE('',*,*,#583,.T.);
#585=DIRECTION('',(0.,1.,0.));
#586=VECTOR('',#585,1.);
#587=CARTESIAN_POINT('',(-3.99999999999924,0.,3.80000000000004));
#588=LINE('',#587,#586);
#589=EDGE_CURVE('E506',#582,#392,#588,.T.);
#590=ORIENTED_EDGE('',*,*,#589,.T.);
#591=ORIENTED_EDGE('',*,*,#393,.F.);
#592=ORIENTED_EDGE('',*,*,#495,.F.);
#593=EDGE_LOOP('',(#552,#560,#568,#576,#584,#590,#591,#592));
#594=FACE_BOUND('',#593,.T.);
#595=ADVANCED_FACE('F704',(#594),#544,.F.);
#596=CARTESIAN_POINT('',(-3.99999999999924,0.,3.80000000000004));
#597=DIRECTION('',(-1.,0.,0.));
#598=DIRECTION('',(0.,0.,1.));
#599=AXIS2_PLACEMENT_3D('',#596,#597,#598);
#600=PLANE('',#599);
#601=ORIENTED_EDGE('',*,*,#399,.F.);
#602=ORIENTED_EDGE('',*,*,#589,.F.);
#603=DIRECTION('',(0.,0.,1.));
#604=VECTOR('',#603,1.);
#605=CARTESIAN_POINT('',(-3.99999999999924,0.,0.));
#606=LINE('',#605,#604);
#607=EDGE_CURVE('E590',#582,#331,#606,.F.);
#608=ORIENTED_EDGE('',*,*,#607,.T.);
#609=ORIENTED_EDGE('',*,*,#332,.F.);
#610=EDGE_LOOP('',(#601,#602,#608,#609));
#611=FACE_BOUND('',#610,.T.);
#612=ADVANCED_FACE('F700',(#611),#600,.F.);
#613=CARTESIAN_POINT('',(-2.04999999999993,0.,6.78417590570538));
#614=DIRECTION('',(-1.,0.,0.));
#615=DIRECTION('',(0.,0.,1.));
#616=AXIS2_PLACEMENT_3D('',#613,#614,#615);
#617=PLANE('',#616);
#618=DIRECTION('',(0.,0.,-1.));
#619=VECTOR('',#618,1.);
#620=CARTESIAN_POINT('',(-2.04999999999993,3.0000000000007,0.));
#621=LINE('',#620,#619);
#622=CARTESIAN_POINT('',(-2.04999999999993,3.0000000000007,5.79999999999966));
#623=VERTEX_POINT('',#622);
#624=EDGE_CURVE('E495',#623,#566,#621,.T.);
#625=ORIENTED_EDGE('',*,*,#624,.F.);
#626=DIRECTION('',(0.,1.,0.));
#627=VECTOR('',#626,1.);
#628=CARTESIAN_POINT('',(-2.04999999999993,0.,5.79999999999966));
#629=LINE('',#628,#627);
#630=CARTESIAN_POINT('',(-2.04999999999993,0.,5.79999999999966));
#631=VERTEX_POINT('',#630);
#632=EDGE_CURVE('E581',#631,#623,#629,.T.);
#633=ORIENTED_EDGE('',*,*,#632,.F.);
#634=DIRECTION('',(0.,0.,1.));
#635=VECTOR('',#634,1.);
#636=CARTESIAN_POINT('',(-2.04999999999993,0.,0.));
#637=LINE('',#636,#635);
#638=EDGE_CURVE('E595',#631,#574,#637,.F.);
#639=ORIENTED_EDGE('',*,*,#638,.T.);
#640=ORIENTED_EDGE('',*,*,#575,.F.);
#641=EDGE_LOOP('',(#625,#633,#639,#640));
#642=FACE_BOUND('',#641,.T.);
#643=ADVANCED_FACE('F696',(#642),#617,.F.);
#644=CARTESIAN_POINT('',(0.,3.0000000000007,0.));
#645=DIRECTION('',(0.,-1.,0.));
#646=DIRECTION('',(0.,0.,-1.));
#647=AXIS2_PLACEMENT_3D('',#644,#645,#646);
#648=PLANE('',#647);
#649=ORIENTED_EDGE('',*,*,#567,.T.);
#650=DIRECTION('',(0.,0.,-1.));
#651=VECTOR('',#650,1.);
#652=CARTESIAN_POINT('',(2.04999999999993,3.0000000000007,3.04286581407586));
#653=LINE('',#652,#651);
#654=CARTESIAN_POINT('',(2.04999999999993,3.0000000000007,5.79999999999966));
#655=VERTEX_POINT('',#654);
#656=EDGE_CURVE('E487',#558,#655,#653,.F.);
#657=ORIENTED_EDGE('',*,*,#656,.T.);
#658=DIRECTION('',(1.,0.,0.));
#659=VECTOR('',#658,1.);
#660=CARTESIAN_POINT('',(-5.60000000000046,3.0000000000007,5.79999999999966));
#661=LINE('',#660,#659);
#662=EDGE_CURVE('E578',#623,#655,#661,.T.);
#663=ORIENTED_EDGE('',*,*,#662,.F.);
#664=ORIENTED_EDGE('',*,*,#624,.T.);
#665=EDGE_LOOP('',(#649,#657,#663,#664));
#666=FACE_BOUND('',#665,.T.);
#667=ADVANCED_FACE('F692',(#666),#648,.T.);
#668=CARTESIAN_POINT('',(2.04999999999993,0.,3.04286581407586));
#669=DIRECTION('',(1.,0.,0.));
#670=DIRECTION('',(0.,0.,-1.));
#671=AXIS2_PLACEMENT_3D('',#668,#669,#670);
#672=PLANE('',#671);
#673=ORIENTED_EDGE('',*,*,#656,.F.);
#674=ORIENTED_EDGE('',*,*,#559,.F.);
#675=DIRECTION('',(0.,0.,1.));
#676=VECTOR('',#675,1.);
#677=CARTESIAN_POINT('',(2.04999999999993,0.,0.));
#678=LINE('',#677,#676);
#679=CARTESIAN_POINT('',(2.04999999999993,0.,5.79999999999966));
#680=VERTEX_POINT('',#679);
#681=EDGE_CURVE('E615',#550,#680,#678,.T.);
#682=ORIENTED_EDGE('',*,*,#681,.T.);
#683=DIRECTION('',(0.,1.,0.));
#684=VECTOR('',#683,1.);
#685=CARTESIAN_POINT('',(2.04999999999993,0.,5.79999999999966));
#686=LINE('',#685,#684);
#687=EDGE_CURVE('E575',#655,#680,#686,.F.);
#688=ORIENTED_EDGE('',*,*,#687,.F.);
#689=EDGE_LOOP('',(#673,#674,#682,#688));
#690=FACE_BOUND('',#689,.T.);
#691=ADVANCED_FACE('F686',(#690),#672,.F.);
#692=CARTESIAN_POINT('',(3.81,7.87999999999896,-5.79999999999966));
#693=DIRECTION('',(0.,0.,-1.));
#694=DIRECTION('',(-1.,0.,0.));
#695=AXIS2_PLACEMENT_3D('',#692,#693,#694);
#696=CYLINDRICAL_SURFACE('',#695,1.59999999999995);
#697=ORIENTED_EDGE('',*,*,#39,.T.);
#698=DIRECTION('',(0.,0.,-1.));
#699=VECTOR('',#698,1.);
#700=CARTESIAN_POINT('',(5.35919333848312,7.48000000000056,-9.3000000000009));
#701=LINE('',#700,#699);
#702=CARTESIAN_POINT('',(5.35919333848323,7.48000000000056,-5.79999999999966));
#703=VERTEX_POINT('',#702);
#704=EDGE_CURVE('E481',#31,#703,#701,.F.);
#705=ORIENTED_EDGE('',*,*,#704,.T.);
#706=CARTESIAN_POINT('',(3.81,7.87999999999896,-5.79999999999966));
#707=DIRECTION('',(0.,0.,-1.));
#708=DIRECTION('',(-1.,0.,0.));
#709=AXIS2_PLACEMENT_3D('',#706,#707,#708);
#710=CIRCLE('',#709,1.59999999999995);
#711=CARTESIAN_POINT('',(2.26080666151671,7.48000000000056,-5.79999999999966));
#712=VERTEX_POINT('',#711);
#713=EDGE_CURVE('E556',#712,#703,#710,.F.);
#714=ORIENTED_EDGE('',*,*,#713,.F.);
#715=DIRECTION('',(0.,0.,-1.));
#716=VECTOR('',#715,1.);
#717=CARTESIAN_POINT('',(2.26080666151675,7.48000000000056,-9.3000000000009));
#718=LINE('',#717,#716);
#719=EDGE_CURVE('E483',#712,#29,#718,.T.);
#720=ORIENTED_EDGE('',*,*,#719,.T.);
#721=EDGE_LOOP('',(#697,#705,#714,#720));
#722=FACE_BOUND('',#721,.T.);
#723=ADVANCED_FACE('F676',(#722),#696,.T.);
#724=CARTESIAN_POINT('',(6.99772335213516,7.48000000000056,-9.3000000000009));
#725=DIRECTION('',(0.,-1.,0.));
#726=DIRECTION('',(0.,0.,-1.));
#727=AXIS2_PLACEMENT_3D('',#724,#725,#726);
#728=PLANE('',#727);
#729=DIRECTION('',(-1.,0.,0.));
#730=VECTOR('',#729,1.);
#731=CARTESIAN_POINT('',(5.60000000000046,7.48000000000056,-5.79999999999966));
#732=LINE('',#731,#730);
#733=EDGE_CURVE('E555',#703,#712,#732,.T.);
#734=ORIENTED_EDGE('',*,*,#733,.F.);
#735=ORIENTED_EDGE('',*,*,#704,.F.);
#736=ORIENTED_EDGE('',*,*,#32,.F.);
#737=ORIENTED_EDGE('',*,*,#719,.F.);
#738=EDGE_LOOP('',(#734,#735,#736,#737));
#739=FACE_BOUND('',#738,.T.);
#740=ADVANCED_FACE('F678',(#739),#728,.F.);
#741=CARTESIAN_POINT('',(-3.81,7.87999999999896,-5.79999999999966));
#742=DIRECTION('',(0.,0.,-1.));
#743=DIRECTION('',(-1.,0.,0.));
#744=AXIS2_PLACEMENT_3D('',#741,#742,#743);
#745=CYLINDRICAL_SURFACE('',#744,1.59999999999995);
#746=ORIENTED_EDGE('',*,*,#64,.T.);
#747=DIRECTION('',(0.,0.,-1.));
#748=VECTOR('',#747,1.);
#749=CARTESIAN_POINT('',(-2.26080666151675,7.48000000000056,-9.3000000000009));
#750=LINE('',#749,#748);
#751=CARTESIAN_POINT('',(-2.26080666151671,7.48000000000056,-5.79999999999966));
#752=VERTEX_POINT('',#751);
#753=EDGE_CURVE('E475',#56,#752,#750,.F.);
#754=ORIENTED_EDGE('',*,*,#753,.T.);
#755=CARTESIAN_POINT('',(-3.81,7.87999999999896,-5.79999999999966));
#756=DIRECTION('',(0.,0.,-1.));
#757=DIRECTION('',(-1.,0.,0.));
#758=AXIS2_PLACEMENT_3D('',#755,#756,#757);
#759=CIRCLE('',#758,1.59999999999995);
#760=CARTESIAN_POINT('',(-5.35919333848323,7.48000000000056,-5.79999999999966));
#761=VERTEX_POINT('',#760);
#762=EDGE_CURVE('E553',#761,#752,#759,.F.);
#763=ORIENTED_EDGE('',*,*,#762,.F.);
#764=DIRECTION('',(0.,0.,-1.));
#765=VECTOR('',#764,1.);
#766=CARTESIAN_POINT('',(-5.35919333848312,7.48000000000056,-9.3000000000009));
#767=LINE('',#766,#765);
#768=EDGE_CURVE('E477',#761,#54,#767,.T.);
#769=ORIENTED_EDGE('',*,*,#768,.T.);
#770=EDGE_LOOP('',(#746,#754,#763,#769));
#771=FACE_BOUND('',#770,.T.);
#772=ADVANCED_FACE('F661',(#771),#745,.T.);
#773=CARTESIAN_POINT('',(6.99772335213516,7.48000000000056,-9.3000000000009));
#774=DIRECTION('',(0.,-1.,0.));
#775=DIRECTION('',(0.,0.,-1.));
#776=AXIS2_PLACEMENT_3D('',#773,#774,#775);
#777=PLANE('',#776);
#778=DIRECTION('',(-1.,0.,0.));
#779=VECTOR('',#778,1.);
#780=CARTESIAN_POINT('',(5.60000000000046,7.48000000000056,-5.79999999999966));
#781=LINE('',#780,#779);
#782=EDGE_CURVE('E552',#752,#761,#781,.T.);
#783=ORIENTED_EDGE('',*,*,#782,.F.);
#784=ORIENTED_EDGE('',*,*,#753,.F.);
#785=ORIENTED_EDGE('',*,*,#57,.F.);
#786=ORIENTED_EDGE('',*,*,#768,.F.);
#787=EDGE_LOOP('',(#783,#784,#785,#786));
#788=FACE_BOUND('',#787,.T.);
#789=ADVANCED_FACE('F657',(#788),#777,.F.);
#790=CARTESIAN_POINT('',(-3.81,7.87999999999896,-5.79999999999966));
#791=DIRECTION('',(0.,0.,-1.));
#792=DIRECTION('',(-1.,0.,0.));
#793=AXIS2_PLACEMENT_3D('',#790,#791,#792);
#794=CYLINDRICAL_SURFACE('',#793,1.59999999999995);
#795=CARTESIAN_POINT('',(-3.81,7.87999999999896,-5.79999999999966));
#796=DIRECTION('',(0.,0.,-1.));
#797=DIRECTION('',(-1.,0.,0.));
#798=AXIS2_PLACEMENT_3D('',#795,#796,#797);
#799=CIRCLE('',#798,1.59999999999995);
#800=CARTESIAN_POINT('',(-2.26080666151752,8.2799999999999,-5.79999999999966));
#801=VERTEX_POINT('',#800);
#802=CARTESIAN_POINT('',(-5.35919333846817,8.2799999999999,-5.79999999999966));
#803=VERTEX_POINT('',#802);
#804=EDGE_CURVE('E549',#801,#803,#799,.F.);
#805=ORIENTED_EDGE('',*,*,#804,.F.);
#806=DIRECTION('',(0.,0.,1.));
#807=VECTOR('',#806,1.);
#808=CARTESIAN_POINT('',(-2.26080666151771,8.2799999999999,-9.3000000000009));
#809=LINE('',#808,#807);
#810=EDGE_CURVE('E277',#801,#93,#809,.F.);
#811=ORIENTED_EDGE('',*,*,#810,.T.);
#812=ORIENTED_EDGE('',*,*,#94,.T.);
#813=DIRECTION('',(0.,0.,1.));
#814=VECTOR('',#813,1.);
#815=CARTESIAN_POINT('',(-5.35919333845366,8.2799999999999,-9.3000000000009));
#816=LINE('',#815,#814);
#817=EDGE_CURVE('E473',#84,#803,#816,.T.);
#818=ORIENTED_EDGE('',*,*,#817,.T.);
#819=EDGE_LOOP('',(#805,#811,#812,#818));
#820=FACE_BOUND('',#819,.T.);
#821=ADVANCED_FACE('F885',(#820),#794,.T.);
#822=CARTESIAN_POINT('',(-6.92386875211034,8.2799999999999,-9.3000000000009));
#823=DIRECTION('',(0.,1.,0.));
#824=DIRECTION('',(0.,0.,1.));
#825=AXIS2_PLACEMENT_3D('',#822,#823,#824);
#826=PLANE('',#825);
#827=ORIENTED_EDGE('',*,*,#85,.F.);
#828=ORIENTED_EDGE('',*,*,#154,.F.);
#829=ORIENTED_EDGE('',*,*,#130,.F.);
#830=ORIENTED_EDGE('',*,*,#164,.F.);
#831=ORIENTED_EDGE('',*,*,#105,.F.);
#832=ORIENTED_EDGE('',*,*,#810,.F.);
#833=DIRECTION('',(-1.,0.,0.));
#834=VECTOR('',#833,1.);
#835=CARTESIAN_POINT('',(5.60000000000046,8.2799999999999,-5.79999999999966));
#836=LINE('',#835,#834);
#837=EDGE_CURVE('E548',#803,#801,#836,.F.);
#838=ORIENTED_EDGE('',*,*,#837,.F.);
#839=ORIENTED_EDGE('',*,*,#817,.F.);
#840=EDGE_LOOP('',(#827,#828,#829,#830,#831,#832,#838,#839));
#841=FACE_BOUND('',#840,.T.);
#842=ADVANCED_FACE('F275',(#841),#826,.F.);
#843=CARTESIAN_POINT('',(3.81,7.87999999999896,-5.79999999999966));
#844=DIRECTION('',(0.,0.,-1.));
#845=DIRECTION('',(-1.,0.,0.));
#846=AXIS2_PLACEMENT_3D('',#843,#844,#845);
#847=CYLINDRICAL_SURFACE('',#846,1.59999999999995);
#848=CARTESIAN_POINT('',(3.81,7.87999999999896,-5.79999999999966));
#849=DIRECTION('',(0.,0.,-1.));
#850=DIRECTION('',(-1.,0.,0.));
#851=AXIS2_PLACEMENT_3D('',#848,#849,#850);
#852=CIRCLE('',#851,1.59999999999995);
#853=CARTESIAN_POINT('',(5.35919333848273,8.2799999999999,-5.79999999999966));
#854=VERTEX_POINT('',#853);
#855=CARTESIAN_POINT('',(2.26080666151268,8.2799999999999,-5.79999999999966));
#856=VERTEX_POINT('',#855);
#857=EDGE_CURVE('E544',#854,#856,#852,.F.);
#858=ORIENTED_EDGE('',*,*,#857,.F.);
#859=DIRECTION('',(0.,0.,1.));
#860=VECTOR('',#859,1.);
#861=CARTESIAN_POINT('',(5.35919333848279,8.2799999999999,-9.3000000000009));
#862=LINE('',#861,#860);
#863=EDGE_CURVE('E350',#854,#183,#862,.F.);
#864=ORIENTED_EDGE('',*,*,#863,.T.);
#865=ORIENTED_EDGE('',*,*,#213,.T.);
#866=DIRECTION('',(0.,0.,1.));
#867=VECTOR('',#866,1.);
#868=CARTESIAN_POINT('',(2.26080666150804,8.2799999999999,-9.3000000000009));
#869=LINE('',#868,#867);
#870=EDGE_CURVE('E468',#205,#856,#869,.T.);
#871=ORIENTED_EDGE('',*,*,#870,.T.);
#872=EDGE_LOOP('',(#858,#864,#865,#871));
#873=FACE_BOUND('',#872,.T.);
#874=ADVANCED_FACE('F331',(#873),#847,.T.);
#875=CARTESIAN_POINT('',(-6.92386875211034,8.2799999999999,-9.3000000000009));
#876=DIRECTION('',(0.,1.,0.));
#877=DIRECTION('',(0.,0.,1.));
#878=AXIS2_PLACEMENT_3D('',#875,#876,#877);
#879=PLANE('',#878);
#880=ORIENTED_EDGE('',*,*,#206,.F.);
#881=ORIENTED_EDGE('',*,*,#265,.F.);
#882=ORIENTED_EDGE('',*,*,#231,.F.);
#883=ORIENTED_EDGE('',*,*,#255,.F.);
#884=ORIENTED_EDGE('',*,*,#186,.F.);
#885=ORIENTED_EDGE('',*,*,#863,.F.);
#886=DIRECTION('',(-1.,0.,0.));
#887=VECTOR('',#886,1.);
#888=CARTESIAN_POINT('',(5.60000000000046,8.2799999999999,-5.79999999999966));
#889=LINE('',#888,#887);
#890=EDGE_CURVE('E547',#856,#854,#889,.F.);
#891=ORIENTED_EDGE('',*,*,#890,.F.);
#892=ORIENTED_EDGE('',*,*,#870,.F.);
#893=EDGE_LOOP('',(#880,#881,#882,#883,#884,#885,#891,#892));
#894=FACE_BOUND('',#893,.T.);
#895=ADVANCED_FACE('F326',(#894),#879,.F.);
#896=CARTESIAN_POINT('',(2.9000000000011,0.,-4.80000000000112));
#897=DIRECTION('',(1.,0.,0.));
#898=DIRECTION('',(0.,0.,-1.));
#899=AXIS2_PLACEMENT_3D('',#896,#897,#898);
#900=PLANE('',#899);
#901=DIRECTION('',(0.,1.,0.));
#902=VECTOR('',#901,1.);
#903=CARTESIAN_POINT('',(2.9000000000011,0.,-5.79999999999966));
#904=LINE('',#903,#902);
#905=CARTESIAN_POINT('',(2.9000000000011,1.79999999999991,-5.79999999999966));
#906=VERTEX_POINT('',#905);
#907=CARTESIAN_POINT('',(2.9000000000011,4.80000000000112,-5.79999999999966));
#908=VERTEX_POINT('',#907);
#909=EDGE_CURVE('E643',#906,#908,#904,.T.);
#910=ORIENTED_EDGE('',*,*,#909,.F.);
#911=DIRECTION('',(0.,0.,-1.));
#912=VECTOR('',#911,1.);
#913=CARTESIAN_POINT('',(2.9000000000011,1.79999999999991,-5.79999999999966));
#914=LINE('',#913,#912);
#915=EDGE_CURVE('E602',#906,#520,#914,.F.);
#916=ORIENTED_EDGE('',*,*,#915,.T.);
#917=ORIENTED_EDGE('',*,*,#521,.F.);
#918=DIRECTION('',(0.,0.,1.));
#919=VECTOR('',#918,1.);
#920=CARTESIAN_POINT('',(2.9000000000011,0.,0.));
#921=LINE('',#920,#919);
#922=EDGE_CURVE('E621',#512,#291,#921,.T.);
#923=ORIENTED_EDGE('',*,*,#922,.T.);
#924=ORIENTED_EDGE('',*,*,#292,.F.);
#925=ORIENTED_EDGE('',*,*,#376,.F.);
#926=ORIENTED_EDGE('',*,*,#431,.F.);
#927=DIRECTION('',(0.,0.,1.));
#928=VECTOR('',#927,1.);
#929=CARTESIAN_POINT('',(2.9000000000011,4.80000000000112,-5.79999999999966));
#930=LINE('',#929,#928);
#931=EDGE_CURVE('E431',#424,#908,#930,.F.);
#932=ORIENTED_EDGE('',*,*,#931,.T.);
#933=EDGE_LOOP('',(#910,#916,#917,#923,#924,#925,#926,#932));
#934=FACE_BOUND('',#933,.T.);
#935=ADVANCED_FACE('F330',(#934),#900,.F.);
#936=CARTESIAN_POINT('',(-2.9000000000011,4.80000000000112,-5.79999999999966));
#937=DIRECTION('',(0.,1.,0.));
#938=DIRECTION('',(0.,0.,1.));
#939=AXIS2_PLACEMENT_3D('',#936,#937,#938);
#940=PLANE('',#939);
#941=ORIENTED_EDGE('',*,*,#425,.F.);
#942=DIRECTION('',(0.,0.,1.));
#943=VECTOR('',#942,1.);
#944=CARTESIAN_POINT('',(-2.9000000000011,4.80000000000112,-3.0000000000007));
#945=LINE('',#944,#943);
#946=CARTESIAN_POINT('',(-2.9000000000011,4.80000000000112,-5.79999999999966));
#947=VERTEX_POINT('',#946);
#948=EDGE_CURVE('E429',#416,#947,#945,.F.);
#949=ORIENTED_EDGE('',*,*,#948,.T.);
#950=DIRECTION('',(-1.,0.,0.));
#951=VECTOR('',#950,1.);
#952=CARTESIAN_POINT('',(5.60000000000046,4.80000000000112,-5.79999999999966));
#953=LINE('',#952,#951);
#954=EDGE_CURVE('E641',#908,#947,#953,.T.);
#955=ORIENTED_EDGE('',*,*,#954,.F.);
#956=ORIENTED_EDGE('',*,*,#931,.F.);
#957=EDGE_LOOP('',(#941,#949,#955,#956));
#958=FACE_BOUND('',#957,.T.);
#959=ADVANCED_FACE('F416',(#958),#940,.F.);
#960=CARTESIAN_POINT('',(-2.9000000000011,0.,-3.0000000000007));
#961=DIRECTION('',(-1.,0.,0.));
#962=DIRECTION('',(0.,0.,1.));
#963=AXIS2_PLACEMENT_3D('',#960,#961,#962);
#964=PLANE('',#963);
#965=DIRECTION('',(0.,1.,0.));
#966=VECTOR('',#965,1.);
#967=CARTESIAN_POINT('',(-2.9000000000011,0.,-5.79999999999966));
#968=LINE('',#967,#966);
#969=CARTESIAN_POINT('',(-2.9000000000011,1.79999999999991,-5.79999999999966));
#970=VERTEX_POINT('',#969);
#971=EDGE_CURVE('E441',#947,#970,#968,.F.);
#972=ORIENTED_EDGE('',*,*,#971,.F.);
#973=ORIENTED_EDGE('',*,*,#948,.F.);
#974=ORIENTED_EDGE('',*,*,#417,.F.);
#975=ORIENTED_EDGE('',*,*,#362,.F.);
#976=ORIENTED_EDGE('',*,*,#346,.F.);
#977=DIRECTION('',(0.,0.,1.));
#978=VECTOR('',#977,1.);
#979=CARTESIAN_POINT('',(-2.9000000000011,0.,0.));
#980=LINE('',#979,#978);
#981=EDGE_CURVE('E587',#339,#448,#980,.F.);
#982=ORIENTED_EDGE('',*,*,#981,.T.);
#983=ORIENTED_EDGE('',*,*,#449,.F.);
#984=DIRECTION('',(0.,0.,-1.));
#985=VECTOR('',#984,1.);
#986=CARTESIAN_POINT('',(-2.9000000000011,1.79999999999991,-5.79999999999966));
#987=LINE('',#986,#985);
#988=EDGE_CURVE('E445',#446,#970,#987,.T.);
#989=ORIENTED_EDGE('',*,*,#988,.T.);
#990=EDGE_LOOP('',(#972,#973,#974,#975,#976,#982,#983,#989));
#991=FACE_BOUND('',#990,.T.);
#992=ADVANCED_FACE('F413',(#991),#964,.F.);
#993=CARTESIAN_POINT('',(-1.5000000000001,1.79999999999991,-5.79999999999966));
#994=DIRECTION('',(0.,-1.,0.));
#995=DIRECTION('',(0.,0.,-1.));
#996=AXIS2_PLACEMENT_3D('',#993,#994,#995);
#997=PLANE('',#996);
#998=ORIENTED_EDGE('',*,*,#471,.F.);
#999=DIRECTION('',(0.,0.,1.));
#1000=VECTOR('',#999,1.);
#1001=CARTESIAN_POINT('',(-1.5000000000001,1.79999999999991,-5.79999999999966));
#1002=LINE('',#1001,#1000);
#1003=CARTESIAN_POINT('',(-1.5000000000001,1.79999999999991,-5.79999999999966));
#1004=VERTEX_POINT('',#1003);
#1005=EDGE_CURVE('E624',#464,#1004,#1002,.F.);
#1006=ORIENTED_EDGE('',*,*,#1005,.T.);
#1007=DIRECTION('',(-1.,0.,0.));
#1008=VECTOR('',#1007,1.);
#1009=CARTESIAN_POINT('',(5.60000000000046,1.79999999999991,-5.79999999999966));
#1010=LINE('',#1009,#1008);
#1011=EDGE_CURVE('E632',#970,#1004,#1010,.F.);
#1012=ORIENTED_EDGE('',*,*,#1011,.F.);
#1013=ORIENTED_EDGE('',*,*,#988,.F.);
#1014=EDGE_LOOP('',(#998,#1006,#1012,#1013));
#1015=FACE_BOUND('',#1014,.T.);
#1016=ADVANCED_FACE('F409',(#1015),#997,.F.);
#1017=CARTESIAN_POINT('',(-1.5000000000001,-1.18255143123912,-5.79999999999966));
#1018=DIRECTION('',(-1.,0.,0.));
#1019=DIRECTION('',(0.,0.,1.));
#1020=AXIS2_PLACEMENT_3D('',#1017,#1018,#1019);
#1021=PLANE('',#1020);
#1022=ORIENTED_EDGE('',*,*,#1005,.F.);
#1023=ORIENTED_EDGE('',*,*,#465,.F.);
#1024=DIRECTION('',(0.,0.,1.));
#1025=VECTOR('',#1024,1.);
#1026=CARTESIAN_POINT('',(-1.5000000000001,0.,0.));
#1027=LINE('',#1026,#1025);
#1028=CARTESIAN_POINT('',(-1.5000000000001,0.,-5.79999999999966));
#1029=VERTEX_POINT('',#1028);
#1030=EDGE_CURVE('E598',#456,#1029,#1027,.F.);
#1031=ORIENTED_EDGE('',*,*,#1030,.T.);
#1032=DIRECTION('',(0.,1.,0.));
#1033=VECTOR('',#1032,1.);
#1034=CARTESIAN_POINT('',(-1.5000000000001,0.,-5.79999999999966));
#1035=LINE('',#1034,#1033);
#1036=EDGE_CURVE('E636',#1004,#1029,#1035,.F.);
#1037=ORIENTED_EDGE('',*,*,#1036,.F.);
#1038=EDGE_LOOP('',(#1022,#1023,#1031,#1037));
#1039=FACE_BOUND('',#1038,.T.);
#1040=ADVANCED_FACE('F405',(#1039),#1021,.F.);
#1041=CARTESIAN_POINT('',(5.60000000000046,0.,5.79999999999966));
#1042=DIRECTION('',(1.,0.,0.));
#1043=DIRECTION('',(0.,0.,-1.));
#1044=AXIS2_PLACEMENT_3D('',#1041,#1042,#1043);
#1045=PLANE('',#1044);
#1046=DIRECTION('',(0.,0.,1.));
#1047=VECTOR('',#1046,1.);
#1048=CARTESIAN_POINT('',(5.60000000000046,17.9999999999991,0.));
#1049=LINE('',#1048,#1047);
#1050=CARTESIAN_POINT('',(5.60000000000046,17.9999999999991,5.79999999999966));
#1051=VERTEX_POINT('',#1050);
#1052=CARTESIAN_POINT('',(5.60000000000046,17.9999999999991,-5.79999999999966));
#1053=VERTEX_POINT('',#1052);
#1054=EDGE_CURVE('E558',#1051,#1053,#1049,.F.);
#1055=ORIENTED_EDGE('',*,*,#1054,.F.);
#1056=DIRECTION('',(0.,1.,0.));
#1057=VECTOR('',#1056,1.);
#1058=CARTESIAN_POINT('',(5.60000000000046,0.,5.79999999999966));
#1059=LINE('',#1058,#1057);
#1060=CARTESIAN_POINT('',(5.60000000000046,0.,5.79999999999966));
#1061=VERTEX_POINT('',#1060);
#1062=EDGE_CURVE('E567',#1061,#1051,#1059,.T.);
#1063=ORIENTED_EDGE('',*,*,#1062,.F.);
#1064=DIRECTION('',(0.,0.,1.));
#1065=VECTOR('',#1064,1.);
#1066=CARTESIAN_POINT('',(5.60000000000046,0.,0.));
#1067=LINE('',#1066,#1065);
#1068=CARTESIAN_POINT('',(5.60000000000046,0.,-5.79999999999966));
#1069=VERTEX_POINT('',#1068);
#1070=EDGE_CURVE('E613',#1061,#1069,#1067,.F.);
#1071=ORIENTED_EDGE('',*,*,#1070,.T.);
#1072=DIRECTION('',(0.,1.,0.));
#1073=VECTOR('',#1072,1.);
#1074=CARTESIAN_POINT('',(5.60000000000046,0.,-5.79999999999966));
#1075=LINE('',#1074,#1073);
#1076=EDGE_CURVE('E771',#1053,#1069,#1075,.F.);
#1077=ORIENTED_EDGE('',*,*,#1076,.F.);
#1078=EDGE_LOOP('',(#1055,#1063,#1071,#1077));
#1079=FACE_BOUND('',#1078,.T.);
#1080=ADVANCED_FACE('F401',(#1079),#1045,.T.);
#1081=CARTESIAN_POINT('',(0.,0.,0.));
#1082=DIRECTION('',(0.,1.,0.));
#1083=DIRECTION('',(0.,0.,1.));
#1084=AXIS2_PLACEMENT_3D('',#1081,#1082,#1083);
#1085=PLANE('',#1084);
#1086=DIRECTION('',(0.,0.,-1.));
#1087=VECTOR('',#1086,1.);
#1088=CARTESIAN_POINT('',(1.5000000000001,0.,-5.79999999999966));
#1089=LINE('',#1088,#1087);
#1090=CARTESIAN_POINT('',(1.5000000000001,0.,-5.79999999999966));
#1091=VERTEX_POINT('',#1090);
#1092=EDGE_CURVE('E608',#510,#1091,#1089,.T.);
#1093=ORIENTED_EDGE('',*,*,#1092,.T.);
#1094=DIRECTION('',(-1.,0.,0.));
#1095=VECTOR('',#1094,1.);
#1096=CARTESIAN_POINT('',(5.60000000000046,0.,-5.79999999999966));
#1097=LINE('',#1096,#1095);
#1098=EDGE_CURVE('E768',#1069,#1091,#1097,.T.);
#1099=ORIENTED_EDGE('',*,*,#1098,.F.);
#1100=ORIENTED_EDGE('',*,*,#1070,.F.);
#1101=DIRECTION('',(1.,0.,0.));
#1102=VECTOR('',#1101,1.);
#1103=CARTESIAN_POINT('',(-5.60000000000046,0.,5.79999999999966));
#1104=LINE('',#1103,#1102);
#1105=EDGE_CURVE('E572',#680,#1061,#1104,.T.);
#1106=ORIENTED_EDGE('',*,*,#1105,.F.);
#1107=ORIENTED_EDGE('',*,*,#681,.F.);
#1108=ORIENTED_EDGE('',*,*,#551,.F.);
#1109=ORIENTED_EDGE('',*,*,#489,.F.);
#1110=ORIENTED_EDGE('',*,*,#300,.T.);
#1111=ORIENTED_EDGE('',*,*,#922,.F.);
#1112=ORIENTED_EDGE('',*,*,#513,.F.);
#1113=EDGE_LOOP('',(#1093,#1099,#1100,#1106,#1107,#1108,#1109,#1110,#1111,#1112));
#1114=FACE_BOUND('',#1113,.T.);
#1115=ADVANCED_FACE('F397',(#1114),#1085,.F.);
#1116=CARTESIAN_POINT('',(1.5000000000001,1.79999999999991,-5.79999999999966));
#1117=DIRECTION('',(1.,0.,0.));
#1118=DIRECTION('',(0.,0.,-1.));
#1119=AXIS2_PLACEMENT_3D('',#1116,#1117,#1118);
#1120=PLANE('',#1119);
#1121=DIRECTION('',(0.,0.,-1.));
#1122=VECTOR('',#1121,1.);
#1123=CARTESIAN_POINT('',(1.5000000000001,1.79999999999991,-5.79999999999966));
#1124=LINE('',#1123,#1122);
#1125=CARTESIAN_POINT('',(1.5000000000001,1.79999999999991,-5.79999999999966));
#1126=VERTEX_POINT('',#1125);
#1127=EDGE_CURVE('E600',#528,#1126,#1124,.T.);
#1128=ORIENTED_EDGE('',*,*,#1127,.T.);
#1129=DIRECTION('',(0.,1.,0.));
#1130=VECTOR('',#1129,1.);
#1131=CARTESIAN_POINT('',(1.5000000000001,0.,-5.79999999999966));
#1132=LINE('',#1131,#1130);
#1133=EDGE_CURVE('E763',#1091,#1126,#1132,.T.);
#1134=ORIENTED_EDGE('',*,*,#1133,.F.);
#1135=ORIENTED_EDGE('',*,*,#1092,.F.);
#1136=ORIENTED_EDGE('',*,*,#535,.F.);
#1137=EDGE_LOOP('',(#1128,#1134,#1135,#1136));
#1138=FACE_BOUND('',#1137,.T.);
#1139=ADVANCED_FACE('F393',(#1138),#1120,.F.);
#1140=CARTESIAN_POINT('',(2.9000000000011,1.79999999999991,-5.79999999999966));
#1141=DIRECTION('',(0.,-1.,0.));
#1142=DIRECTION('',(0.,0.,-1.));
#1143=AXIS2_PLACEMENT_3D('',#1140,#1141,#1142);
#1144=PLANE('',#1143);
#1145=ORIENTED_EDGE('',*,*,#529,.T.);
#1146=ORIENTED_EDGE('',*,*,#915,.F.);
#1147=DIRECTION('',(-1.,0.,0.));
#1148=VECTOR('',#1147,1.);
#1149=CARTESIAN_POINT('',(5.60000000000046,1.79999999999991,-5.79999999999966));
#1150=LINE('',#1149,#1148);
#1151=EDGE_CURVE('E760',#1126,#906,#1150,.F.);
#1152=ORIENTED_EDGE('',*,*,#1151,.F.);
#1153=ORIENTED_EDGE('',*,*,#1127,.F.);
#1154=EDGE_LOOP('',(#1145,#1146,#1152,#1153));
#1155=FACE_BOUND('',#1154,.T.);
#1156=ADVANCED_FACE('F389',(#1155),#1144,.F.);
#1157=CARTESIAN_POINT('',(0.,0.,0.));
#1158=DIRECTION('',(0.,1.,0.));
#1159=DIRECTION('',(0.,0.,1.));
#1160=AXIS2_PLACEMENT_3D('',#1157,#1158,#1159);
#1161=PLANE('',#1160);
#1162=ORIENTED_EDGE('',*,*,#981,.F.);
#1163=ORIENTED_EDGE('',*,*,#340,.T.);
#1164=ORIENTED_EDGE('',*,*,#607,.F.);
#1165=ORIENTED_EDGE('',*,*,#583,.F.);
#1166=ORIENTED_EDGE('',*,*,#638,.F.);
#1167=DIRECTION('',(1.,0.,0.));
#1168=VECTOR('',#1167,1.);
#1169=CARTESIAN_POINT('',(-5.60000000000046,0.,5.79999999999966));
#1170=LINE('',#1169,#1168);
#1171=CARTESIAN_POINT('',(-5.60000000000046,0.,5.79999999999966));
#1172=VERTEX_POINT('',#1171);
#1173=EDGE_CURVE('E584',#1172,#631,#1170,.T.);
#1174=ORIENTED_EDGE('',*,*,#1173,.F.);
#1175=DIRECTION('',(0.,0.,1.));
#1176=VECTOR('',#1175,1.);
#1177=CARTESIAN_POINT('',(-5.60000000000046,0.,-5.79999999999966));
#1178=LINE('',#1177,#1176);
#1179=CARTESIAN_POINT('',(-5.60000000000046,0.,-5.79999999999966));
#1180=VERTEX_POINT('',#1179);
#1181=EDGE_CURVE('E755',#1180,#1172,#1178,.T.);
#1182=ORIENTED_EDGE('',*,*,#1181,.F.);
#1183=DIRECTION('',(-1.,0.,0.));
#1184=VECTOR('',#1183,1.);
#1185=CARTESIAN_POINT('',(5.60000000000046,0.,-5.79999999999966));
#1186=LINE('',#1185,#1184);
#1187=EDGE_CURVE('E775',#1029,#1180,#1186,.T.);
#1188=ORIENTED_EDGE('',*,*,#1187,.F.);
#1189=ORIENTED_EDGE('',*,*,#1030,.F.);
#1190=ORIENTED_EDGE('',*,*,#457,.T.);
#1191=EDGE_LOOP('',(#1162,#1163,#1164,#1165,#1166,#1174,#1182,#1188,#1189,#1190));
#1192=FACE_BOUND('',#1191,.T.);
#1193=ADVANCED_FACE('F385',(#1192),#1161,.F.);
#1194=CARTESIAN_POINT('',(-5.60000000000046,0.,5.79999999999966));
#1195=DIRECTION('',(0.,0.,1.));
#1196=DIRECTION('',(1.,0.,0.));
#1197=AXIS2_PLACEMENT_3D('',#1194,#1195,#1196);
#1198=PLANE('',#1197);
#1199=ORIENTED_EDGE('',*,*,#1105,.T.);
#1200=ORIENTED_EDGE('',*,*,#1062,.T.);
#1201=DIRECTION('',(1.,0.,0.));
#1202=VECTOR('',#1201,1.);
#1203=CARTESIAN_POINT('',(0.,17.9999999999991,5.79999999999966));
#1204=LINE('',#1203,#1202);
#1205=CARTESIAN_POINT('',(-5.60000000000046,17.9999999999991,5.79999999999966));
#1206=VERTEX_POINT('',#1205);
#1207=EDGE_CURVE('E562',#1206,#1051,#1204,.T.);
#1208=ORIENTED_EDGE('',*,*,#1207,.F.);
#1209=DIRECTION('',(0.,1.,0.));
#1210=VECTOR('',#1209,1.);
#1211=CARTESIAN_POINT('',(-5.60000000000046,0.,5.79999999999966));
#1212=LINE('',#1211,#1210);
#1213=EDGE_CURVE('E758',#1172,#1206,#1212,.T.);
#1214=ORIENTED_EDGE('',*,*,#1213,.F.);
#1215=ORIENTED_EDGE('',*,*,#1173,.T.);
#1216=ORIENTED_EDGE('',*,*,#632,.T.);
#1217=ORIENTED_EDGE('',*,*,#662,.T.);
#1218=ORIENTED_EDGE('',*,*,#687,.T.);
#1219=EDGE_LOOP('',(#1199,#1200,#1208,#1214,#1215,#1216,#1217,#1218));
#1220=FACE_BOUND('',#1219,.T.);
#1221=ADVANCED_FACE('F382',(#1220),#1198,.T.);
#1222=CARTESIAN_POINT('',(0.,17.9999999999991,0.));
#1223=DIRECTION('',(0.,1.,0.));
#1224=DIRECTION('',(0.,0.,1.));
#1225=AXIS2_PLACEMENT_3D('',#1222,#1223,#1224);
#1226=PLANE('',#1225);
#1227=ORIENTED_EDGE('',*,*,#1054,.T.);
#1228=DIRECTION('',(-1.,0.,0.));
#1229=VECTOR('',#1228,1.);
#1230=CARTESIAN_POINT('',(5.60000000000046,17.9999999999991,-5.79999999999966));
#1231=LINE('',#1230,#1229);
#1232=CARTESIAN_POINT('',(-5.60000000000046,17.9999999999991,-5.79999999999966));
#1233=VERTEX_POINT('',#1232);
#1234=EDGE_CURVE('E40',#1233,#1053,#1231,.F.);
#1235=ORIENTED_EDGE('',*,*,#1234,.F.);
#1236=DIRECTION('',(0.,0.,1.));
#1237=VECTOR('',#1236,1.);
#1238=CARTESIAN_POINT('',(-5.60000000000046,17.9999999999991,-5.79999999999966));
#1239=LINE('',#1238,#1237);
#1240=EDGE_CURVE('E31',#1206,#1233,#1239,.F.);
#1241=ORIENTED_EDGE('',*,*,#1240,.F.);
#1242=ORIENTED_EDGE('',*,*,#1207,.T.);
#1243=EDGE_LOOP('',(#1227,#1235,#1241,#1242));
#1244=FACE_BOUND('',#1243,.T.);
#1245=ADVANCED_FACE('F375',(#1244),#1226,.T.);
#1246=CARTESIAN_POINT('',(5.60000000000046,0.,-5.79999999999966));
#1247=DIRECTION('',(0.,0.,-1.));
#1248=DIRECTION('',(-1.,0.,0.));
#1249=AXIS2_PLACEMENT_3D('',#1246,#1247,#1248);
#1250=PLANE('',#1249);
#1251=ORIENTED_EDGE('',*,*,#1133,.T.);
#1252=ORIENTED_EDGE('',*,*,#1151,.T.);
#1253=ORIENTED_EDGE('',*,*,#909,.T.);
#1254=ORIENTED_EDGE('',*,*,#954,.T.);
#1255=ORIENTED_EDGE('',*,*,#971,.T.);
#1256=ORIENTED_EDGE('',*,*,#1011,.T.);
#1257=ORIENTED_EDGE('',*,*,#1036,.T.);
#1258=ORIENTED_EDGE('',*,*,#1187,.T.);
#1259=DIRECTION('',(0.,1.,0.));
#1260=VECTOR('',#1259,1.);
#1261=CARTESIAN_POINT('',(-5.60000000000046,0.,-5.79999999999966));
#1262=LINE('',#1261,#1260);
#1263=EDGE_CURVE('E11',#1233,#1180,#1262,.F.);
#1264=ORIENTED_EDGE('',*,*,#1263,.F.);
#1265=ORIENTED_EDGE('',*,*,#1234,.T.);
#1266=ORIENTED_EDGE('',*,*,#1076,.T.);
#1267=ORIENTED_EDGE('',*,*,#1098,.T.);
#1268=EDGE_LOOP('',(#1251,#1252,#1253,#1254,#1255,#1256,#1257,#1258,#1264,#1265,#1266,#1267));
#1269=FACE_BOUND('',#1268,.T.);
#1270=ORIENTED_EDGE('',*,*,#857,.T.);
#1271=ORIENTED_EDGE('',*,*,#890,.T.);
#1272=EDGE_LOOP('',(#1270,#1271));
#1273=FACE_BOUND('',#1272,.T.);
#1274=ORIENTED_EDGE('',*,*,#804,.T.);
#1275=ORIENTED_EDGE('',*,*,#837,.T.);
#1276=EDGE_LOOP('',(#1274,#1275));
#1277=FACE_BOUND('',#1276,.T.);
#1278=ORIENTED_EDGE('',*,*,#762,.T.);
#1279=ORIENTED_EDGE('',*,*,#782,.T.);
#1280=EDGE_LOOP('',(#1278,#1279));
#1281=FACE_BOUND('',#1280,.T.);
#1282=ORIENTED_EDGE('',*,*,#713,.T.);
#1283=ORIENTED_EDGE('',*,*,#733,.T.);
#1284=EDGE_LOOP('',(#1282,#1283));
#1285=FACE_BOUND('',#1284,.T.);
#1286=ADVANCED_FACE('F369',(#1269,#1273,#1277,#1281,#1285),#1250,.T.);
#1287=CARTESIAN_POINT('',(-5.60000000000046,0.,-5.79999999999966));
#1288=DIRECTION('',(-1.,0.,0.));
#1289=DIRECTION('',(0.,0.,1.));
#1290=AXIS2_PLACEMENT_3D('',#1287,#1288,#1289);
#1291=PLANE('',#1290);
#1292=ORIENTED_EDGE('',*,*,#1240,.T.);
#1293=ORIENTED_EDGE('',*,*,#1263,.T.);
#1294=ORIENTED_EDGE('',*,*,#1181,.T.);
#1295=ORIENTED_EDGE('',*,*,#1213,.T.);
#1296=EDGE_LOOP('',(#1292,#1293,#1294,#1295));
#1297=FACE_BOUND('',#1296,.T.);
#1298=ADVANCED_FACE('F367',(#1297),#1291,.T.);
#1299=CLOSED_SHELL('',(#43,#68,#116,#141,#169,#217,#242,#270,#310,#350,#404,#435,#475,#499,#539,
#595,#612,#643,#667,#691,#723,#740,#772,#789,#821,#842,#874,#895,#935,#959,#992,#1016,#1040,
#1080,#1115,#1139,#1156,#1193,#1221,#1245,#1286,#1298));
#1300=MANIFOLD_SOLID_BREP('B1',#1299);
#1301=ADVANCED_BREP_SHAPE_REPRESENTATION('',(#18,#1300),#14);
#1302=SHAPE_DEFINITION_REPRESENTATION(#9,#1301);
ENDSEC;
END-ISO-10303-21;
